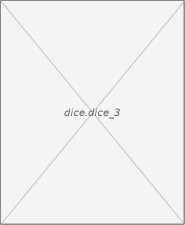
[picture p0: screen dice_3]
VISUALIZATION dice_3  // 185x225
VAR_IN_OUT
VAR_IN_OUT
	
END_VAR
    Image (0,0 185x225), image: dice.dice_3
END_VISUALIZATION
